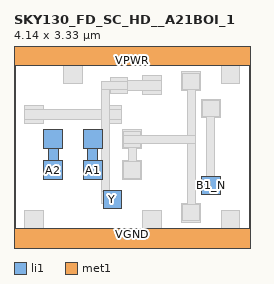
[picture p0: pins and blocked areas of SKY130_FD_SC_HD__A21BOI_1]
MACRO SKY130_FD_SC_HD__A21BOI_1
 CLASS CORE ;
 FOREIGN SKY130_FD_SC_HD__A21BOI_1 0 0 ;
 SIZE 4.14 BY 3.33 ;
 ORIGIN 0 0 ;
 SYMMETRY X Y R90 ;
 SITE unit ;
  PIN VPWR
   DIRECTION INOUT ;
   USE POWER ;
   SHAPE ABUTMENT ;
    PORT
     CLASS CORE ;
       LAYER li1 ;
        RECT 0.00000000 3.09000000 4.14000000 3.57000000 ;
       LAYER met1 ;
        RECT 0.00000000 3.09000000 4.14000000 3.57000000 ;
    END
  END VPWR

  PIN VGND
   DIRECTION INOUT ;
   USE POWER ;
   SHAPE ABUTMENT ;
    PORT
     CLASS CORE ;
       LAYER li1 ;
        RECT 0.00000000 -0.24000000 4.14000000 0.24000000 ;
       LAYER met1 ;
        RECT 0.00000000 -0.24000000 4.14000000 0.24000000 ;
    END
  END VGND

  PIN Y
   DIRECTION INOUT ;
   USE SIGNAL ;
   SHAPE ABUTMENT ;
    PORT
     CLASS CORE ;
       LAYER li1 ;
        RECT 1.56000000 0.58000000 1.89000000 0.91000000 ;
    END
  END Y

  PIN A2
   DIRECTION INOUT ;
   USE SIGNAL ;
   SHAPE ABUTMENT ;
    PORT
     CLASS CORE ;
       LAYER li1 ;
        RECT 0.52500000 1.09500000 0.85500000 1.42500000 ;
        RECT 0.60500000 1.42500000 0.77500000 1.63500000 ;
        RECT 0.52500000 1.63500000 0.85500000 1.96500000 ;
    END
  END A2

  PIN B1_N
   DIRECTION INOUT ;
   USE SIGNAL ;
   SHAPE ABUTMENT ;
    PORT
     CLASS CORE ;
       LAYER li1 ;
        RECT 3.28500000 0.82500000 3.61500000 1.15500000 ;
    END
  END B1_N

  PIN A1
   DIRECTION INOUT ;
   USE SIGNAL ;
   SHAPE ABUTMENT ;
    PORT
     CLASS CORE ;
       LAYER li1 ;
        RECT 1.21500000 1.09500000 1.54500000 1.42500000 ;
        RECT 1.29500000 1.42500000 1.46500000 1.63500000 ;
        RECT 1.21500000 1.63500000 1.54500000 1.96500000 ;
    END
  END A1

 OBS
    LAYER polycont ;
     RECT 3.36500000 0.90500000 3.53500000 1.07500000 ;
     RECT 3.36500000 2.25500000 3.53500000 2.42500000 ;
     RECT 0.60500000 1.17500000 0.77500000 1.34500000 ;
     RECT 0.60500000 1.71500000 0.77500000 1.88500000 ;
     RECT 1.29500000 1.17500000 1.46500000 1.34500000 ;
     RECT 1.29500000 1.71500000 1.46500000 1.88500000 ;
     RECT 1.98500000 1.17500000 2.15500000 1.34500000 ;
     RECT 1.98500000 1.71500000 2.15500000 1.88500000 ;

    LAYER pdiffc ;
     RECT 2.33000000 2.66000000 2.50000000 2.83000000 ;
     RECT 0.95000000 2.86000000 1.12000000 3.03000000 ;
     RECT 3.71000000 2.86000000 3.88000000 3.03000000 ;
     RECT 0.26000000 2.15000000 0.43000000 2.32000000 ;
     RECT 1.64000000 2.15000000 1.81000000 2.32000000 ;
     RECT 3.02000000 2.73000000 3.19000000 2.90000000 ;

    LAYER ndiffc ;
     RECT 1.64000000 0.66000000 1.81000000 0.83000000 ;
     RECT 0.26000000 0.30000000 0.43000000 0.47000000 ;
     RECT 2.33000000 0.30000000 2.50000000 0.47000000 ;
     RECT 3.71000000 0.30000000 3.88000000 0.47000000 ;
     RECT 3.02000000 0.43000000 3.19000000 0.60000000 ;

    LAYER li1 ;
     RECT 1.56000000 0.58000000 1.89000000 0.91000000 ;
     RECT 2.25000000 2.58000000 2.58000000 2.66000000 ;
     RECT 1.75500000 2.66000000 2.58000000 2.83000000 ;
     RECT 2.25000000 2.83000000 2.58000000 2.91000000 ;
     RECT 3.28500000 0.82500000 3.61500000 1.15500000 ;
     RECT 3.28500000 2.17500000 3.61500000 2.50500000 ;
     RECT 0.52500000 1.09500000 0.85500000 1.42500000 ;
     RECT 0.60500000 1.42500000 0.77500000 1.63500000 ;
     RECT 0.52500000 1.63500000 0.85500000 1.96500000 ;
     RECT 0.87000000 2.78000000 1.20000000 3.09000000 ;
     RECT 3.63000000 2.78000000 3.96000000 3.09000000 ;
     RECT 0.00000000 3.09000000 4.14000000 3.57000000 ;
     RECT 0.18000000 2.07000000 0.51000000 2.15000000 ;
     RECT 1.56000000 2.07000000 1.89000000 2.15000000 ;
     RECT 0.18000000 2.15000000 1.89000000 2.32000000 ;
     RECT 0.18000000 2.32000000 0.51000000 2.40000000 ;
     RECT 1.56000000 2.32000000 1.89000000 2.40000000 ;
     RECT 1.21500000 1.09500000 1.54500000 1.42500000 ;
     RECT 1.29500000 1.42500000 1.46500000 1.63500000 ;
     RECT 1.21500000 1.63500000 1.54500000 1.96500000 ;
     RECT 0.00000000 -0.24000000 4.14000000 0.24000000 ;
     RECT 0.18000000 0.24000000 0.51000000 0.55000000 ;
     RECT 2.25000000 0.24000000 2.58000000 0.55000000 ;
     RECT 3.63000000 0.24000000 3.96000000 0.55000000 ;
     RECT 2.94000000 0.35000000 3.27000000 0.68000000 ;
     RECT 1.90500000 1.09500000 2.23500000 1.42500000 ;
     RECT 1.90500000 1.63500000 2.23500000 1.96500000 ;
     RECT 2.94000000 2.65000000 3.27000000 2.98000000 ;

    LAYER viali ;
     RECT 1.64000000 0.66000000 1.81000000 0.83000000 ;
     RECT 1.75500000 2.66000000 1.92500000 2.83000000 ;
     RECT 3.36500000 0.90500000 3.53500000 1.07500000 ;
     RECT 3.36500000 2.25500000 3.53500000 2.42500000 ;
     RECT 0.95000000 3.24500000 1.12000000 3.41500000 ;
     RECT 0.26000000 -0.08500000 0.43000000 0.08500000 ;
     RECT 3.02000000 0.43000000 3.19000000 0.60000000 ;
     RECT 1.98500000 1.17500000 2.15500000 1.34500000 ;
     RECT 1.98500000 1.71500000 2.15500000 1.88500000 ;
     RECT 3.02000000 2.73000000 3.19000000 2.90000000 ;

    LAYER met1 ;
     RECT 1.68000000 2.60000000 1.69500000 2.67500000 ;
     RECT 1.58000000 0.60000000 1.87000000 0.67500000 ;
     RECT 1.54000000 0.67500000 1.87000000 0.89000000 ;
     RECT 1.54000000 0.89000000 1.68000000 2.67500000 ;
     RECT 1.69500000 2.60000000 1.98500000 2.67500000 ;
     RECT 1.54000000 2.67500000 1.98500000 2.81500000 ;
     RECT 1.69500000 2.81500000 1.98500000 2.89000000 ;
     RECT 3.30500000 0.84500000 3.59500000 1.13500000 ;
     RECT 3.38000000 1.13500000 3.52000000 2.19500000 ;
     RECT 3.30500000 2.19500000 3.59500000 2.48500000 ;
     RECT 0.00000000 3.09000000 4.14000000 3.57000000 ;
     RECT 0.00000000 -0.24000000 4.14000000 0.24000000 ;
     RECT 2.96000000 0.37000000 3.25000000 0.66000000 ;
     RECT 1.92500000 1.11500000 2.21500000 1.40500000 ;
     RECT 2.00000000 1.40500000 2.14000000 1.65500000 ;
     RECT 1.92500000 1.65500000 2.21500000 1.73000000 ;
     RECT 3.03500000 0.66000000 3.17500000 1.73000000 ;
     RECT 1.92500000 1.73000000 3.17500000 1.87000000 ;
     RECT 1.92500000 1.87000000 2.21500000 1.94500000 ;
     RECT 3.03500000 1.87000000 3.17500000 2.67000000 ;
     RECT 2.96000000 2.67000000 3.25000000 2.96000000 ;

    LAYER via ;


    LAYER met2 ;


    LAYER via2 ;


    LAYER met3 ;


 END
END SKY130_FD_SC_HD__A21BOI_1
